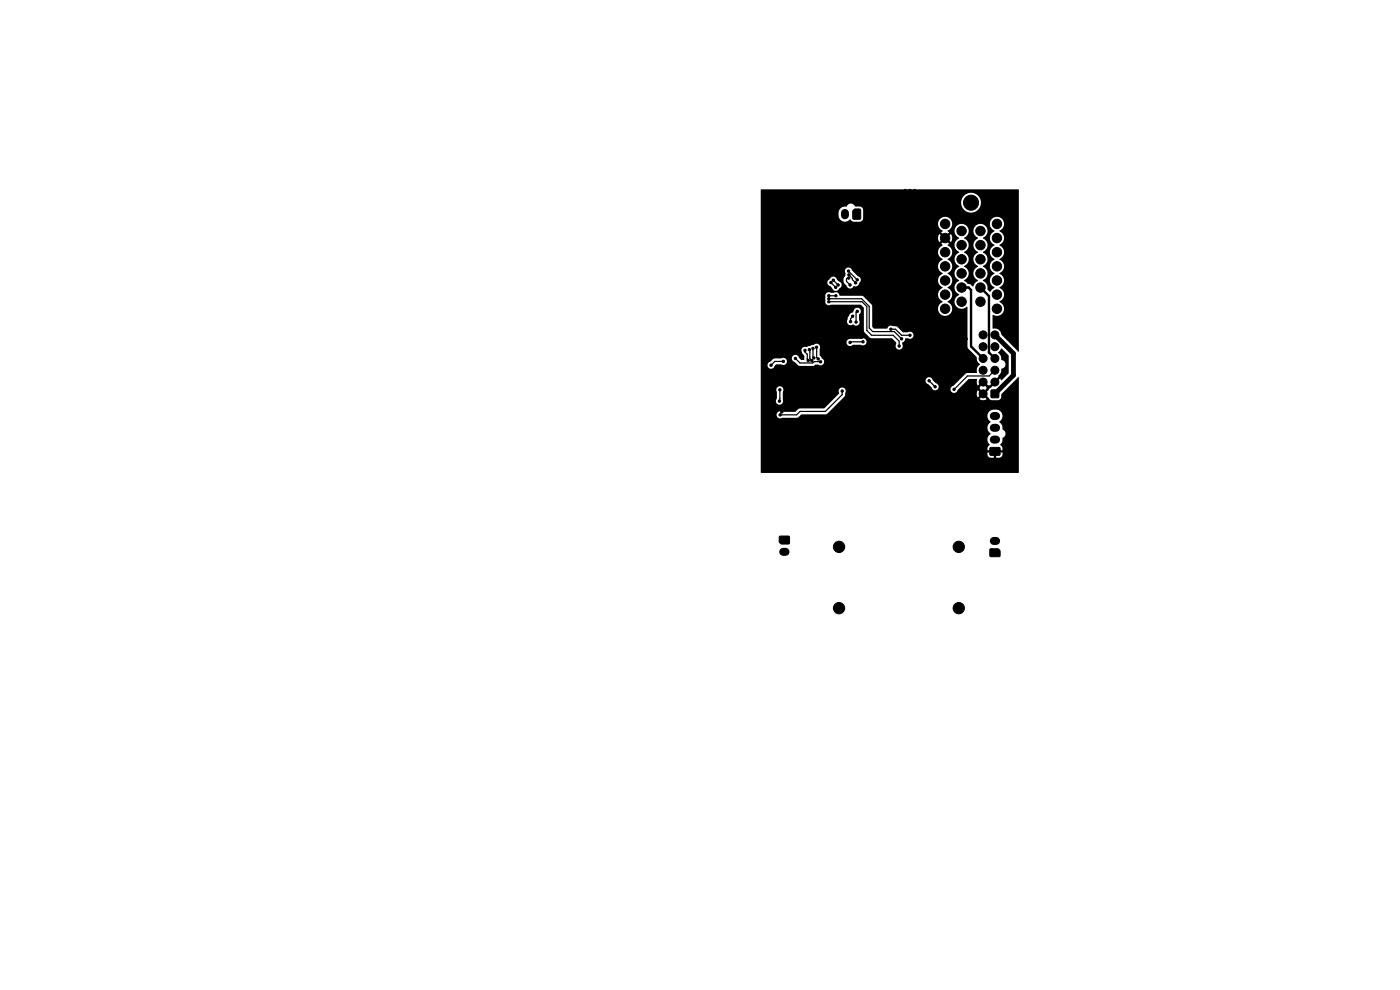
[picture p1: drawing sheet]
<svg xmlns="http://www.w3.org/2000/svg" width="297mm" height="210mm" viewBox="0 0 297 210" stroke-linecap="round" stroke-linejoin="round" font-family="sans-serif">
<g fill="#000" stroke="#000" stroke-width=".21">
<path d="M181 44.7l.4-.4 1.1 .1v2.1h-1.5zM210.3 82.8h1.5v1.5h-1.5zM210 95h2.1v1.5h-2.1zM165.4 113.8h2v1.5h-1.8l-.3-.4zM210 116.5h1.8l.4 .4-.1 1.1h-2.1z"/>
<circle cx="172.2" cy="57.4" r=".25"/>
<circle cx="175.8" cy="56.6" r=".25"/>
<circle cx="176.3" cy="59.9" r=".25"/>
<circle cx="176.8" cy="59.4" r=".25"/>
<circle cx="178.5" cy="56" r=".25"/>
<circle cx="180" cy="57.5" r=".25"/>
<circle cx="180.1" cy="59" r=".25"/>
<circle cx="180.1" cy="58.3" r=".25"/>
<circle cx="181" cy="52" r=".25"/>
<circle cx="181.5" cy="60" r=".25"/>
<circle cx="181.9" cy="59.4" r=".25"/>
<circle cx="185.2" cy="54.9" r=".25"/>
<circle cx="185.4" cy="53.8" r=".25"/>
<circle cx="185.9" cy="58.4" r=".25"/>
<circle cx="185.9" cy="53.3" r=".25"/>
<circle cx="186.7" cy="53.3" r=".25"/>
<circle cx="187.5" cy="53.3" r=".25"/>
<circle cx="188" cy="54.6" r=".25"/>
<circle cx="188" cy="53.8" r=".25"/>
<circle cx="188.5" cy="53.3" r=".25"/>
<circle cx="189.5" cy="53.3" r=".25"/>
<circle cx="189.5" cy="57.4" r=".25"/>
<circle cx="191" cy="42.2" r=".25"/>
<circle cx="191" cy="41.1" r=".25"/>
<circle cx="192" cy="42.2" r=".25"/>
<circle cx="192" cy="41.1" r=".25"/>
<circle cx="192" cy="40.4" r=".25"/>
<circle cx="193" cy="43.7" r=".25"/>
<circle cx="193" cy="40.4" r=".25"/>
<circle cx="193" cy="41.1" r=".25"/>
<circle cx="193" cy="42.2" r=".25"/>
<circle cx="194.1" cy="41.1" r=".25"/>
<circle cx="194.1" cy="40.4" r=".25"/>
<circle cx="195.1" cy="56.4" r=".25"/>
<circle cx="195.1" cy="57.4" r=".25"/>
<circle cx="196.1" cy="58.4" r=".25"/>
<circle cx="196.1" cy="56.4" r=".25"/>
<circle cx="196.1" cy="57.4" r=".25"/>
<circle cx="196.6" cy="52.6" r=".25"/>
<circle cx="196.6" cy="51.1" r=".25"/>
<circle cx="196.6" cy="51.8" r=".25"/>
<circle cx="197.1" cy="56.4" r=".25"/>
<circle cx="197.1" cy="57.4" r=".25"/>
<circle cx="197.1" cy="58.4" r=".25"/>
<circle cx="197.4" cy="51.8" r=".25"/>
<circle cx="197.4" cy="52.6" r=".25"/>
<circle cx="197.4" cy="51.1" r=".25"/>
<circle cx="198.1" cy="52.6" r=".25"/>
<circle cx="198.1" cy="56.4" r=".25"/>
<circle cx="198.1" cy="58.4" r=".25"/>
<circle cx="198.1" cy="51.8" r=".25"/>
<circle cx="198.1" cy="51.1" r=".25"/>
<circle cx="198.1" cy="57.4" r=".25"/>
<circle cx="199.4" cy="51.8" r=".25"/>
<circle cx="200.5" cy="53.5" r="1"/>
<circle cx="200.5" cy="59.5" r="1"/>
<circle cx="200.5" cy="50.5" r="1"/>
<circle cx="200.5" cy="56.5" r="1"/>
<circle cx="200.5" cy="47.5" r="1"/>
<circle cx="204" cy="55" r="1"/>
<circle cx="204" cy="49" r="1"/>
<circle cx="204" cy="52" r="1"/>
<circle cx="204" cy="58" r="1"/>
<circle cx="206" cy="43" r="1.6"/>
<circle cx="208" cy="49" r="1"/>
<circle cx="208" cy="55" r="1"/>
<circle cx="208" cy="52" r="1"/>
<circle cx="208" cy="58" r="1"/>
<circle cx="211.5" cy="59.5" r="1"/>
<circle cx="211.5" cy="53.5" r="1"/>
<circle cx="211.5" cy="50.5" r="1"/>
<circle cx="211.5" cy="56.5" r="1"/>
<circle cx="211.5" cy="47.5" r="1"/>
<circle cx="163.6" cy="77.5" r=".25"/>
<circle cx="163.8" cy="72.6" r=".25"/>
<circle cx="165.1" cy="77.7" r=".25"/>
<circle cx="166.1" cy="72.1" r=".25"/>
<circle cx="166.2" cy="76.7" r=".25"/>
<circle cx="168.7" cy="76" r=".25"/>
<circle cx="169.7" cy="71.9" r=".25"/>
<circle cx="170.8" cy="74.3" r=".25"/>
<circle cx="171.4" cy="76.5" r=".25"/>
<circle cx="171.7" cy="74.2" r=".25"/>
<circle cx="172.2" cy="76.5" r=".25"/>
<circle cx="172.5" cy="73.9" r=".25"/>
<circle cx="172.7" cy="75.9" r=".25"/>
<circle cx="173.2" cy="73.7" r=".25"/>
<circle cx="173.6" cy="76.1" r=".25"/>
<circle cx="174.1" cy="76.7" r=".25"/>
<circle cx="174.2" cy="64.5" r=".25"/>
<circle cx="174.2" cy="60.7" r=".25"/>
<circle cx="174.2" cy="63.2" r=".25"/>
<circle cx="175.8" cy="64" r=".25"/>
<circle cx="175.8" cy="63.4" r=".25"/>
<circle cx="175.8" cy="62.7" r=".25"/>
<circle cx="176.6" cy="73.8" r=".25"/>
<circle cx="177.3" cy="61" r=".25"/>
<circle cx="177.3" cy="62.7" r=".25"/>
<circle cx="177.8" cy="60.5" r=".25"/>
<circle cx="178.1" cy="75.7" r=".25"/>
<circle cx="180.3" cy="75.7" r=".25"/>
<circle cx="180.3" cy="72.6" r=".25"/>
<circle cx="180.3" cy="60.5" r=".25"/>
<circle cx="180.4" cy="68.2" r=".25"/>
<circle cx="180.9" cy="67.1" r=".25"/>
<circle cx="181.6" cy="68.3" r=".25"/>
<circle cx="181.9" cy="69.8" r=".25"/>
<circle cx="181.9" cy="66" r=".25"/>
<circle cx="182.8" cy="71.5" r=".25"/>
<circle cx="183.1" cy="72.5" r=".25"/>
<circle cx="189" cy="79.2" r=".25"/>
<circle cx="189" cy="77.5" r=".25"/>
<circle cx="189" cy="69.8" r=".25"/>
<circle cx="190.5" cy="65.3" r=".25"/>
<circle cx="190.8" cy="73.4" r=".25"/>
<circle cx="191.3" cy="71.9" r=".25"/>
<circle cx="193" cy="71.1" r=".25"/>
<circle cx="194.1" cy="60.5" r=".25"/>
<circle cx="195.5" cy="65.5" r=".25"/>
<circle cx="197.4" cy="77.7" r=".25"/>
<circle cx="200.5" cy="62.5" r="1"/>
<circle cx="200.5" cy="65.5" r="1"/>
<circle cx="201.5" cy="74.5" r=".25"/>
<circle cx="204" cy="61" r="1"/>
<circle cx="204" cy="64" r="1"/>
<circle cx="204.5" cy="73" r=".25"/>
<circle cx="205" cy="71.9" r=".25"/>
<circle cx="208" cy="61" r="1"/>
<circle cx="208" cy="64" r="1"/>
<circle cx="208.6" cy="76" r=".85"/>
<circle cx="208.6" cy="73.5" r=".85"/>
<circle cx="208.6" cy="78.5" r=".85"/>
<circle cx="208.6" cy="71" r=".85"/>
<circle cx="211.1" cy="76" r=".85"/>
<circle cx="211.1" cy="73.5" r=".85"/>
<circle cx="211.1" cy="78.5" r=".85"/>
<circle cx="211.1" cy="71" r=".85"/>
<circle cx="211.5" cy="62.5" r="1"/>
<circle cx="211.5" cy="65.5" r="1"/>
<circle cx="163.6" cy="81" r=".25"/>
<circle cx="165.4" cy="85.1" r=".25"/>
<circle cx="165.4" cy="82.7" r=".25"/>
<circle cx="165.5" cy="88" r=".25"/>
<circle cx="165.9" cy="87.4" r=".25"/>
<circle cx="172" cy="98" r=".25"/>
<circle cx="178.7" cy="83" r=".25"/>
<circle cx="180.3" cy="83.1" r=".25"/>
<circle cx="189" cy="97.5" r=".25"/>
<circle cx="189" cy="81.3" r=".25"/>
<circle cx="194.6" cy="95.8" r=".25"/>
<circle cx="197.1" cy="80.8" r=".25"/>
<circle cx="198.4" cy="82" r=".25"/>
<circle cx="200" cy="81.5" r=".25"/>
<circle cx="201.7" cy="95.5" r=".25"/>
<circle cx="202.4" cy="82.6" r=".25"/>
<circle cx="204.5" cy="99.3" r=".25"/>
<circle cx="206" cy="82" r=".25"/>
<circle cx="206" cy="83" r=".25"/>
<circle cx="206" cy="84" r=".25"/>
<circle cx="206.2" cy="93" r=".25"/>
<circle cx="208.6" cy="81" r=".85"/>
<circle cx="208.6" cy="83.5" r=".85"/>
<circle cx="211" cy="98.5" r=".25"/>
<circle cx="211.1" cy="81" r=".85"/>
<circle cx="178" cy="116" r="1.2"/>
<circle cx="203.4" cy="116" r="1.2"/>
<circle cx="178" cy="129" r="1.2"/>
<circle cx="203.4" cy="129" r="1.2"/>
</g>
<path d="M179.2 45.2v.5M210.8 93.3h.5M210.8 90.8h.5M210.8 88.3h.5M166.1 117.1h.5M210.8 114.8h.5" fill="none" stroke="#000" stroke-width="1.7"/>
<path d="M204 61h1.5l.5 .5v12l2.6 2.5M208 61l1.8 1.8v12l1.3 1.2" fill="none" stroke="#000" stroke-width=".51"/>
<path d="M211.1 71l3.9 4v4.6l-3.9 3.9" fill="none" stroke="#000" stroke-width="1"/>
<g fill="none" stroke="#000" stroke-width=".25">
<path d="M176.3 59.9l1 1.1M176.8 59.4l1 1.1M180 57.5l1.9 1.9M180.1 59l-.5 .2v.5l.7 .8M180.1 58.3h.1M180.1 58.3l1.4 1.7M166.3 76.7h-1.9l-.8 .8M168.7 76l1 1h2.7l.3-.3h1.4M170.8 74.3v.4l.5 .5v1.1l.1 .2M171.7 74.2l.1 1.9 .4 .4M172.5 73.9v1.8l.2 .2M173.2 73.7l.1 2.1 .3 .3"/>
<path d="M175.9 62.7h1.5M175.9 64h7l1 1v5.1l1 1h4.6l1.3 1.3v1M175.9 63.4h6.9l1.6 1.6v4.6l.7 .7h4.6l1.6 1.6M181 67.1l-.6 .5v.6M181.9 66l-.3 .3v2M183.1 72.5h-2.6l-.2 .1M189 69.8h1l1.3 1.3h1.7M211.1 78.5l-1.3 1.3h-4.6l-2.8 2.8M165.4 82.7v2.3M178.7 83v.7l-3.6 3.6h-5.4l-.7 .7h-3.5M197.1 80.8l1.3 1.2"/>
</g>
<path d="M161.4 40.2h54.7v34.4h-.2l-3.5-3.6a1.5 1.5 0 0 0-1.8-1.3v-2.9a1.76 1.76 0 0 0 2.4-.9v-.3a1.72 1.72 0 0 0-1-1.6 1.63 1.63 0 0 0 1-1.5 1.63 1.63 0 0 0-1-1.5 1.63 1.63 0 0 0 1-1.5 1.63 1.63 0 0 0-1-1.5 1.63 1.63 0 0 0 1-1.5 1.63 1.63 0 0 0-1-1.5 1.63 1.63 0 0 0 1-1.5 1.63 1.63 0 0 0-1-1.5 1.63 1.63 0 0 0 1-1.5 1.63 1.63 0 0 0-1-1.5 1.52 1.52 0 0 0 .9-2.2 1.52 1.52 0 0 0-2.3-.4 1.52 1.52 0 0 0 .1 2.4l.3 .2a1.63 1.63 0 0 0-1 1.5 1.63 1.63 0 0 0 1 1.5 1.63 1.63 0 0 0-1 1.5 1.63 1.63 0 0 0 1 1.5 1.63 1.63 0 0 0-1 1.5 1.63 1.63 0 0 0 1 1.5 1.63 1.63 0 0 0-1 1.5 1.63 1.63 0 0 0 1 1.5l-1 .9-.5-.5v-.5a1.75 1.75 0 0 0-1-1.4 1.63 1.63 0 0 0 1-1.5 1.63 1.63 0 0 0-1-1.5 1.63 1.63 0 0 0 1-1.5 1.63 1.63 0 0 0-1-1.5 1.63 1.63 0 0 0 1-1.5 1.63 1.63 0 0 0-1-1.5 1.53 1.53 0 0 0 .9-2.2 1.53 1.53 0 0 0-2.2-.5 1.53 1.53 0 0 0-.2 2.3l.5 .5a1.59 1.59 0 0 0-1 1.4 1.59 1.59 0 0 0 1 1.5 1.63 1.63 0 0 0-1 1.5 1.63 1.63 0 0 0 1 1.5 1.63 1.63 0 0 0-1 1.5 1.63 1.63 0 0 0 1 1.5l-.1 .1a1.85 1.85 0 0 0-1 1.2l-.5-.5-.6-.1-.8-.7a1.63 1.63 0 0 0 1-1.5 1.63 1.63 0 0 0-1-1.5 1.63 1.63 0 0 0 1-1.5 1.63 1.63 0 0 0-1-1.5 1.63 1.63 0 0 0 1-1.5 1.63 1.63 0 0 0-1-1.5 1.53 1.53 0 0 0 .9-2.2 1.53 1.53 0 0 0-2.2-.5 1.53 1.53 0 0 0-.2 2.3l.5 .5a1.59 1.59 0 0 0-1 1.4 1.59 1.59 0 0 0 1 1.5 1.63 1.63 0 0 0-1 1.5 1.63 1.63 0 0 0 1 1.5 1.63 1.63 0 0 0-1 1.5 1.63 1.63 0 0 0 1 1.5 1.63 1.63 0 0 0-1 1.5 1.63 1.63 0 0 0 1 1.5 1.56 1.56 0 0 0-.8 2.3 1.56 1.56 0 0 0 2.5 .3l.1 8.6 1.9 2 .1 .9 .6 .6-.1 .2a1.54 1.54 0 0 0-.6 1.7l-2.3 .1-2.7 2.7a.76 .76 0 0 0-.3 1.3 .76 .76 0 0 0 1.3-.5l2.3-2.3h1.7l.1 .1-.1 .9 .2 .4 .6-.5 .3 .3-.5 .5v.3l.5 .6-.3 .3-.6-.5a1.33 1.33 0 0 0 0 1.5l.6-.5 .3 .3-.4 .6a1.34 1.34 0 0 0 1.4 0l-.5-.6 .3-.3 .9 .9 .3 .2h1.4l.4-.2 .3-.4v-.7l3.6-3.6h.1v20.3h-54.6l-.1-.1v-12.3h3.3a.78 .78 0 0 0 .4 .8 .78 .78 0 0 0 .9-.1h3.1l.6-.5h39.8l.2 .9 .5 .5a1.55 1.55 0 0 0 0 2.5 1.5 1.5 0 0 0-.2 2.4l-.5 .4v.7h1v.5h-1l.1 .8 .5 .3h.7v-.8h.5v.8h.7a.83 .83 0 0 0 .7-1.1h-1.1v-.5h1.1l-.1-.7-.4-.5a1.81 1.81 0 0 0 .5-1.4 .99 .99 0 0 0 .6-1 .99 .99 0 0 0-.6-.9 1.63 1.63 0 0 0-.7-1.5 1.38 1.38 0 0 0 .7-1.5 1.38 1.38 0 0 0-1.3-1.1h-.7a1.35 1.35 0 0 0-1.2 1.2h-39.8l.3-.2 5.4-.1 3.9-3.9a1.54 1.54 0 0 0-.3-1.6 .83 .83 0 0 0-.9 .2 .83 .83 0 0 0-.1 1l-3.2 3.1h-5.1l-1 .8-2.8-.1a.76 .76 0 0 0-1.2 .6h-3.3v-2.9h3.2v.2a.76 .76 0 0 0 .9 .6 .76 .76 0 0 0 .6-1v-1.7a.76 .76 0 0 0-.7-1.2 .76 .76 0 0 0-.6 1.3v1.3l-.2 .5h-3.2v-4.3h34.9a.8 .8 0 0 0 .7 .8l.6 .7a.76 .76 0 0 0 1.3 .3 .76 .76 0 0 0-.4-1.2l-.7-.7a.76 .76 0 0 0-.8-.6 .76 .76 0 0 0-.7 .7h-34.9v-3.3h1.4v.1a.77 .77 0 0 0 .8 .7 .77 .77 0 0 0 .7-.6l.4-.3h1a.77 .77 0 0 0 1.1-.2 .77 .77 0 0 0-.4-1.1h1.6l.2 .5 1.4 1.1h2.9l.5-.3 .6 .1a.8 .8 0 0 0 1.2-.4 .8 .8 0 0 0-.5-1.1l-.4-.5v-1.4a.81 .81 0 0 0-.3-1 .81 .81 0 0 0-1.1 .2l-1.3 .4a.9 .9 0 0 0-1.1 .3 .9 .9 0 0 0 .2 1.2l.3 .4v.8l-.6 .1-.5-.5a.76 .76 0 0 0-.8-.6 .76 .76 0 0 0-.7 .7l-3.8 .1-1.1 .8-.3 .5h-1.4v-4.8h18.2a.79 .79 0 0 0 .5 .8 .79 .79 0 0 0 .9-.3l1.7 .1a.76 .76 0 0 0 1.1-.7 .76 .76 0 0 0-1.2-.6h-2.2a.76 .76 0 0 0-.8 .7h-18.2v-4.5h18.3v.2a.89 .89 0 0 0 1.4 .5 .77 .77 0 0 0 1 .1 .77 .77 0 0 0 .1-1l.1-1.2a.79 .79 0 0 0-.2-1.4 .79 .79 0 0 0-1.1 .8v.2a1.21 1.21 0 0 0-1 .9l-.3 .9h-18.3v-5.4h13.7v.9a.79 .79 0 0 0 .2 1 .79 .79 0 0 0 1 0l6.3 .1 .7 .6v4.9l.1 .3 1.3 1.2 4.5 .1 .9 .8v.4a.76 .76 0 0 0 .7 1.2 .76 .76 0 0 0 .6-1.3v-.2l.4-.3 .2-.6 .6-.1a.77 .77 0 0 0 1.2-.6 .77 .77 0 0 0-1.2-.6h-1.1l-1.2-1.2-.8-.1a.92 .92 0 0 0-1.4 .5h-2.6l-.4-.3-.1-4.6-1.8-1.9-.4-.2h-4.7a.82 .82 0 0 0-1.2-.6h-.7a.76 .76 0 0 0-1.1 .6h-13.7v-2.8h14.1l.2 .5 .8 .7a.8 .8 0 0 0 .8 .6 .8 .8 0 0 0 .8-.5 .77 .77 0 0 0 .5-.8 .77 .77 0 0 0-.7-.7l-.4-.6h1.5v.9l.6 .6a.82 .82 0 0 0 .7 .6 .82 .82 0 0 0 .8-.5 .87 .87 0 0 0 1.2-.8 .78 .78 0 0 0 .3-.7 .78 .78 0 0 0-.6-.6l-1.3-1.3a.78 .78 0 0 0-1.1-.5 .78 .78 0 0 0-.2 1.2l-.1 .5-.3 .6h-1.5a.86 .86 0 0 0-.9-.4 .86 .86 0 0 0-.7 .6l-.4 .6h-14.1v-12.5h37.6a1.72 1.72 0 0 0 1 1.6l-.4 .3 .6 .6-.3 .3-.7-.5a1.49 1.49 0 0 0 .1 1.7l.6-.6 .3 .3-.6 .6 .4 .4a1.59 1.59 0 0 0-1 1.4 1.59 1.59 0 0 0 1 1.5 1.63 1.63 0 0 0-1 1.5 1.63 1.63 0 0 0 1 1.5 1.63 1.63 0 0 0-1 1.5 1.63 1.63 0 0 0 1 1.5 1.63 1.63 0 0 0-1 1.5 1.63 1.63 0 0 0 1 1.5 1.55 1.55 0 0 0-.7 2.4 1.55 1.55 0 0 0 2.5 0 1.55 1.55 0 0 0-.8-2.4 1.63 1.63 0 0 0 1-1.5 1.63 1.63 0 0 0-1-1.5 1.63 1.63 0 0 0 1-1.5 1.63 1.63 0 0 0-1-1.5 1.63 1.63 0 0 0 1-1.5 1.63 1.63 0 0 0-1-1.5 1.63 1.63 0 0 0 1-1.5 1.63 1.63 0 0 0-1-1.5l.4-.3-.6-.6 .3-.3 .7 .5a1.49 1.49 0 0 0-.1-1.7l-.6 .6-.3-.3 .6-.6-.4-.4a1.51 1.51 0 0 0 .4-2.6 1.51 1.51 0 0 0-2.4 1.1h-37.6v-2.3h16.5v.7a1.42 1.42 0 0 0 1 1.2 1.42 1.42 0 0 0 1.5-.5l.4 .4 .3 .1h1.4l.5-.4v-2.4l-.5-.4h-1.1a1 1 0 0 0-1-.6 1 1 0 0 0-.9 .6h-.1a1.35 1.35 0 0 0-1.5 1.3h-16.5v-2.2h42.5v.2a2.11 2.11 0 0 0 3.2 1.7 2.11 2.11 0 0 0 0-3.6 2.11 2.11 0 0 0-3.2 1.7h-42.5zM212.4 73.9h.1l1.5 1.5v3.7l-1.5 1.5h-.1l-.2-.3-.6 .5-.3-.3 .5-.6v-.2a1.97 1.97 0 0 0 .7-1.5 .96 .96 0 0 0 .8-1 .96 .96 0 0 0-.9-.9v-.1a1.64 1.64 0 0 0-.7-1.4zM209.1 81.3l.6 .5h.2l.6-.5 .3 .3-1.7 1.7-.3-.3 .5-.6v-.2l-.5-.6z" fill="#000"/>
</svg>
